VERSION 5.7 ;

UNITS
  TIME NANOSECONDS 1 ;
  CAPACITANCE PICOFARADS 1 ;
  RESISTANCE OHMS 1 ;
  DATABASE MICRONS 1000 ;
END UNITS

MANUFACTURINGGRID 0.005 ;
USEMINSPACING OBS OFF ;

PROPERTYDEFINITIONS
  LAYER LEF58_TYPE STRING ;
END PROPERTYDEFINITIONS

SITE unithd
  SYMMETRY Y ;
  CLASS CORE ;
  SIZE 0.46 BY 2.72 ;
END unithd

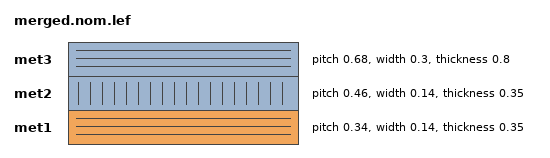
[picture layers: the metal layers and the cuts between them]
LAYER met1
  TYPE ROUTING ;
  DIRECTION HORIZONTAL ;

  PITCH 0.34 ;
  OFFSET 0.17 ;

  WIDTH 0.14 ;                     # Met1 1
  # SPACING 0.14 ;                 # Met1 2
  # SPACING 0.28 RANGE 3.001 100 ; # Met1 3b
  SPACINGTABLE
     PARALLELRUNLENGTH 0
     WIDTH 0 0.14
     WIDTH 3 0.28 ;
  AREA 0.083 ;                     # Met1 6
  THICKNESS 0.35 ;
  MINENCLOSEDAREA 0.14 ;

  ANTENNAMODEL OXIDE1 ;
  ANTENNADIFFSIDEAREARATIO PWL ( ( 0 400 ) ( 0.0125 400 ) ( 0.0225 2609 ) ( 22.5 11600 ) ) ;

  EDGECAPACITANCE 40.567E-6 ;
  CAPACITANCE CPERSQDIST 25.7784E-6 ;
  DCCURRENTDENSITY AVERAGE 2.8 ; # mA/um Iavg_max at Tj = 90oC
  ACCURRENTDENSITY RMS 6.1 ; # mA/um Irms_max at Tj = 90oC
  MAXIMUMDENSITY 70 ;
  DENSITYCHECKWINDOW 700 700 ;
  DENSITYCHECKSTEP 70 ;

  RESISTANCE RPERSQ 0.125 ;
END met1

LAYER met2
  TYPE ROUTING ;
  DIRECTION VERTICAL ;

  PITCH 0.46 ;
  OFFSET 0.23 ;

  WIDTH 0.14 ;                        # Met2 1
  # SPACING  0.14 ;                   # Met2 2
  # SPACING  0.28 RANGE 3.001 100 ;   # Met2 3b
  SPACINGTABLE
     PARALLELRUNLENGTH 0
     WIDTH 0 0.14
     WIDTH 3 0.28 ;
  AREA 0.0676 ;                       # Met2 6
  THICKNESS 0.35 ;
  MINENCLOSEDAREA 0.14 ;

  EDGECAPACITANCE 37.759E-6 ;
  CAPACITANCE CPERSQDIST 16.9423E-6 ;
  RESISTANCE RPERSQ 0.125 ;
  DCCURRENTDENSITY AVERAGE 2.8 ; # mA/um Iavg_max at Tj = 90oC
  ACCURRENTDENSITY RMS 6.1 ; # mA/um Irms_max at Tj = 90oC

  ANTENNAMODEL OXIDE1 ;
  ANTENNADIFFSIDEAREARATIO PWL ( ( 0 400 ) ( 0.0125 400 ) ( 0.0225 2609 ) ( 22.5 11600 ) ) ;

  MAXIMUMDENSITY 70 ;
  DENSITYCHECKWINDOW 700 700 ;
  DENSITYCHECKSTEP 70 ;
END met2

LAYER met3
  TYPE ROUTING ;
  DIRECTION HORIZONTAL ;

  PITCH 0.68 ;
  OFFSET 0.34 ;

  WIDTH 0.3 ;              # Met3 1
  # SPACING 0.3 ;          # Met3 2
  SPACINGTABLE
     PARALLELRUNLENGTH 0
     WIDTH 0 0.3
     WIDTH 3 0.4 ;
  AREA 0.24 ;              # Met3 6
  THICKNESS 0.8 ;

  EDGECAPACITANCE 40.989E-6 ;
  CAPACITANCE CPERSQDIST 12.3729E-6 ;
  RESISTANCE RPERSQ 0.047 ;
  DCCURRENTDENSITY AVERAGE 6.8 ; # mA/um Iavg_max at Tj = 90oC
  ACCURRENTDENSITY RMS 14.9 ; # mA/um Irms_max at Tj = 90oC

  ANTENNAMODEL OXIDE1 ;
  ANTENNADIFFSIDEAREARATIO PWL ( ( 0 400 ) ( 0.0125 400 ) ( 0.0225 2609 ) ( 22.5 11600 ) ) ;

  MAXIMUMDENSITY 70 ;
  DENSITYCHECKWINDOW 700 700 ;
  DENSITYCHECKSTEP 70 ;
END met3

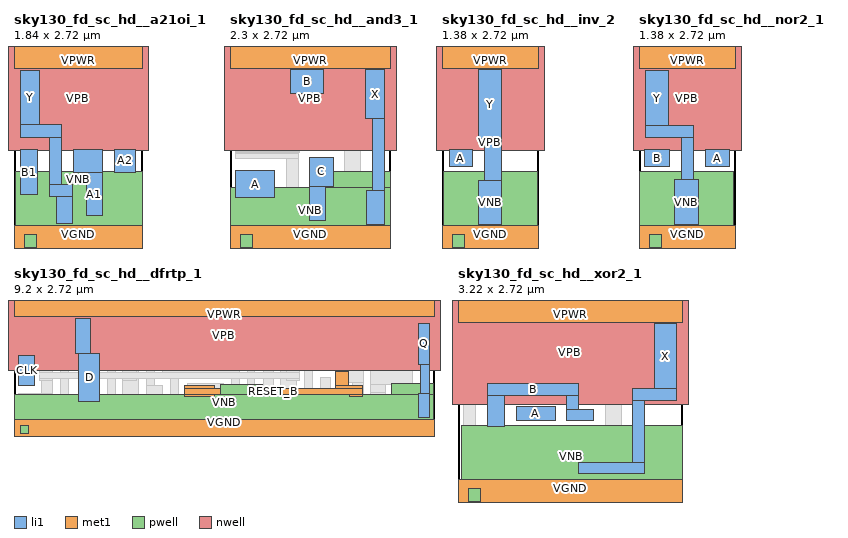
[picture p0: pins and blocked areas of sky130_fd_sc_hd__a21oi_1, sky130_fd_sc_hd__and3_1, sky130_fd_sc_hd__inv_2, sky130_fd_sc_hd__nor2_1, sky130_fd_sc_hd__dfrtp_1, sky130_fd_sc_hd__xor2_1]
MACRO sky130_fd_sc_hd__a21oi_1
  CLASS CORE ;
  FOREIGN sky130_fd_sc_hd__a21oi_1 ;
  ORIGIN 0.000 0.000 ;
  SIZE 1.840 BY 2.720 ;
  SYMMETRY X Y R90 ;
  SITE unithd ;
  PIN A1
    DIRECTION INPUT ;
    USE SIGNAL ;
    ANTENNAGATEAREA 0.247500 ;
    PORT
      LAYER li1 ;
        RECT 0.850 0.995 1.265 1.325 ;
        RECT 1.035 0.375 1.265 0.995 ;
    END
  END A1
  PIN A2
    DIRECTION INPUT ;
    USE SIGNAL ;
    ANTENNAGATEAREA 0.247500 ;
    PORT
      LAYER li1 ;
        RECT 1.445 0.995 1.740 1.325 ;
    END
  END A2
  PIN B1
    DIRECTION INPUT ;
    USE SIGNAL ;
    ANTENNAGATEAREA 0.247500 ;
    PORT
      LAYER li1 ;
        RECT 0.095 0.675 0.335 1.325 ;
    END
  END B1
  PIN VGND
    DIRECTION INOUT ;
    USE GROUND ;
    SHAPE ABUTMENT ;
    PORT
      LAYER met1 ;
        RECT 0.000 -0.240 1.840 0.240 ;
    END
  END VGND
  PIN VNB
    DIRECTION INOUT ;
    USE GROUND ;
    PORT
      LAYER pwell ;
        RECT 0.020 0.105 1.835 1.015 ;
        RECT 0.145 -0.085 0.315 0.105 ;
    END
  END VNB
  PIN VPB
    DIRECTION INOUT ;
    USE POWER ;
    PORT
      LAYER nwell ;
        RECT -0.190 1.305 2.030 2.910 ;
    END
  END VPB
  PIN VPWR
    DIRECTION INOUT ;
    USE POWER ;
    SHAPE ABUTMENT ;
    PORT
      LAYER met1 ;
        RECT 0.000 2.480 1.840 2.960 ;
    END
  END VPWR
  PIN Y
    DIRECTION OUTPUT ;
    USE SIGNAL ;
    ANTENNADIFFAREA 0.447000 ;
    PORT
      LAYER li1 ;
        RECT 0.095 1.685 0.370 2.455 ;
        RECT 0.095 1.495 0.680 1.685 ;
        RECT 0.505 0.825 0.680 1.495 ;
        RECT 0.505 0.645 0.835 0.825 ;
        RECT 0.610 0.265 0.835 0.645 ;
    END
  END Y
  OBS
      LAYER li1 ;
        RECT 0.000 2.635 1.840 2.805 ;
        RECT 0.540 2.025 0.870 2.455 ;
        RECT 1.040 2.195 1.235 2.635 ;
        RECT 1.415 2.025 1.745 2.455 ;
        RECT 0.540 1.855 1.745 2.025 ;
        RECT 0.850 1.525 1.745 1.855 ;
        RECT 0.110 0.085 0.440 0.475 ;
        RECT 1.445 0.085 1.745 0.815 ;
        RECT 0.000 -0.085 1.840 0.085 ;
      LAYER mcon ;
        RECT 0.145 2.635 0.315 2.805 ;
        RECT 0.605 2.635 0.775 2.805 ;
        RECT 1.065 2.635 1.235 2.805 ;
        RECT 1.525 2.635 1.695 2.805 ;
        RECT 0.145 -0.085 0.315 0.085 ;
        RECT 0.605 -0.085 0.775 0.085 ;
        RECT 1.065 -0.085 1.235 0.085 ;
        RECT 1.525 -0.085 1.695 0.085 ;
  END
END sky130_fd_sc_hd__a21oi_1

MACRO sky130_fd_sc_hd__and3_1
  CLASS CORE ;
  FOREIGN sky130_fd_sc_hd__and3_1 ;
  ORIGIN 0.000 0.000 ;
  SIZE 2.300 BY 2.720 ;
  SYMMETRY X Y R90 ;
  SITE unithd ;
  PIN A
    DIRECTION INPUT ;
    USE SIGNAL ;
    ANTENNAGATEAREA 0.126000 ;
    PORT
      LAYER li1 ;
        RECT 0.085 0.635 0.635 1.020 ;
    END
  END A
  PIN B
    DIRECTION INPUT ;
    USE SIGNAL ;
    ANTENNAGATEAREA 0.126000 ;
    PORT
      LAYER li1 ;
        RECT 0.865 2.125 1.345 2.465 ;
    END
  END B
  PIN C
    DIRECTION INPUT ;
    USE SIGNAL ;
    ANTENNAGATEAREA 0.126000 ;
    PORT
      LAYER li1 ;
        RECT 1.145 0.790 1.475 1.215 ;
        RECT 1.145 0.305 1.365 0.790 ;
    END
  END C
  PIN VGND
    DIRECTION INOUT ;
    USE GROUND ;
    SHAPE ABUTMENT ;
    PORT
      LAYER met1 ;
        RECT 0.000 -0.240 2.300 0.240 ;
    END
  END VGND
  PIN VNB
    DIRECTION INOUT ;
    USE GROUND ;
    PORT
      LAYER pwell ;
        RECT 1.375 0.785 2.295 1.015 ;
        RECT 0.005 0.105 2.295 0.785 ;
        RECT 0.145 -0.085 0.315 0.105 ;
    END
  END VNB
  PIN VPB
    DIRECTION INOUT ;
    USE POWER ;
    PORT
      LAYER nwell ;
        RECT -0.190 1.305 2.490 2.910 ;
    END
  END VPB
  PIN VPWR
    DIRECTION INOUT ;
    USE POWER ;
    SHAPE ABUTMENT ;
    PORT
      LAYER met1 ;
        RECT 0.000 2.480 2.300 2.960 ;
    END
  END VPWR
  PIN X
    DIRECTION OUTPUT ;
    USE SIGNAL ;
    ANTENNADIFFAREA 0.429000 ;
    PORT
      LAYER li1 ;
        RECT 1.940 1.765 2.215 2.465 ;
        RECT 2.045 0.735 2.215 1.765 ;
        RECT 1.955 0.255 2.215 0.735 ;
    END
  END X
  OBS
      LAYER li1 ;
        RECT 0.000 2.635 2.300 2.805 ;
        RECT 0.085 2.080 0.690 2.635 ;
        RECT 1.515 2.090 1.770 2.635 ;
        RECT 0.085 1.980 0.700 2.080 ;
        RECT 0.515 1.955 0.700 1.980 ;
        RECT 0.085 1.360 0.345 1.810 ;
        RECT 0.515 1.710 0.845 1.955 ;
        RECT 1.015 1.635 1.770 1.885 ;
        RECT 1.000 1.600 1.770 1.635 ;
        RECT 0.985 1.590 1.770 1.600 ;
        RECT 0.980 1.575 1.875 1.590 ;
        RECT 0.960 1.560 1.875 1.575 ;
        RECT 0.940 1.550 1.875 1.560 ;
        RECT 0.915 1.540 1.875 1.550 ;
        RECT 0.845 1.510 1.875 1.540 ;
        RECT 0.825 1.480 1.875 1.510 ;
        RECT 0.805 1.450 1.875 1.480 ;
        RECT 0.775 1.425 1.875 1.450 ;
        RECT 0.740 1.390 1.875 1.425 ;
        RECT 0.710 1.385 1.875 1.390 ;
        RECT 0.710 1.380 1.100 1.385 ;
        RECT 0.710 1.370 1.075 1.380 ;
        RECT 0.710 1.365 1.060 1.370 ;
        RECT 0.710 1.360 1.045 1.365 ;
        RECT 0.085 1.355 1.045 1.360 ;
        RECT 0.085 1.345 1.035 1.355 ;
        RECT 0.085 1.340 1.025 1.345 ;
        RECT 0.085 1.330 1.015 1.340 ;
        RECT 0.085 1.320 1.010 1.330 ;
        RECT 0.085 1.315 1.005 1.320 ;
        RECT 0.085 1.300 0.995 1.315 ;
        RECT 0.085 1.285 0.990 1.300 ;
        RECT 0.085 1.260 0.980 1.285 ;
        RECT 0.085 1.190 0.975 1.260 ;
        RECT 0.805 0.465 0.975 1.190 ;
        RECT 1.645 0.990 1.875 1.385 ;
        RECT 0.085 0.295 0.975 0.465 ;
        RECT 1.535 0.085 1.785 0.625 ;
        RECT 0.000 -0.085 2.300 0.085 ;
      LAYER mcon ;
        RECT 0.145 2.635 0.315 2.805 ;
        RECT 0.605 2.635 0.775 2.805 ;
        RECT 1.065 2.635 1.235 2.805 ;
        RECT 1.525 2.635 1.695 2.805 ;
        RECT 1.985 2.635 2.155 2.805 ;
        RECT 0.145 -0.085 0.315 0.085 ;
        RECT 0.605 -0.085 0.775 0.085 ;
        RECT 1.065 -0.085 1.235 0.085 ;
        RECT 1.525 -0.085 1.695 0.085 ;
        RECT 1.985 -0.085 2.155 0.085 ;
  END
END sky130_fd_sc_hd__and3_1

MACRO sky130_fd_sc_hd__inv_2
  CLASS CORE ;
  FOREIGN sky130_fd_sc_hd__inv_2 ;
  ORIGIN 0.000 0.000 ;
  SIZE 1.380 BY 2.720 ;
  SYMMETRY X Y R90 ;
  SITE unithd ;
  PIN A
    DIRECTION INPUT ;
    USE SIGNAL ;
    ANTENNAGATEAREA 0.495000 ;
    PORT
      LAYER li1 ;
        RECT 0.105 1.075 0.435 1.325 ;
    END
  END A
  PIN VGND
    DIRECTION INOUT ;
    USE GROUND ;
    SHAPE ABUTMENT ;
    PORT
      LAYER met1 ;
        RECT 0.000 -0.240 1.380 0.240 ;
    END
  END VGND
  PIN VNB
    DIRECTION INOUT ;
    USE GROUND ;
    PORT
      LAYER pwell ;
        RECT 0.015 0.105 1.365 1.015 ;
        RECT 0.145 -0.085 0.315 0.105 ;
    END
  END VNB
  PIN VPB
    DIRECTION INOUT ;
    USE POWER ;
    PORT
      LAYER nwell ;
        RECT -0.190 1.305 1.570 2.910 ;
    END
  END VPB
  PIN VPWR
    DIRECTION INOUT ;
    USE POWER ;
    SHAPE ABUTMENT ;
    PORT
      LAYER met1 ;
        RECT 0.000 2.480 1.380 2.960 ;
    END
  END VPWR
  PIN Y
    DIRECTION OUTPUT ;
    USE SIGNAL ;
    ANTENNADIFFAREA 0.445500 ;
    PORT
      LAYER li1 ;
        RECT 0.525 1.485 0.855 2.465 ;
        RECT 0.605 0.885 0.855 1.485 ;
        RECT 0.525 0.255 0.855 0.885 ;
    END
  END Y
  OBS
      LAYER li1 ;
        RECT 0.000 2.635 1.380 2.805 ;
        RECT 0.125 1.495 0.355 2.635 ;
        RECT 1.025 1.495 1.235 2.635 ;
        RECT 0.125 0.085 0.355 0.905 ;
        RECT 1.025 0.085 1.235 0.905 ;
        RECT 0.000 -0.085 1.380 0.085 ;
      LAYER mcon ;
        RECT 0.145 2.635 0.315 2.805 ;
        RECT 0.605 2.635 0.775 2.805 ;
        RECT 1.065 2.635 1.235 2.805 ;
        RECT 0.145 -0.085 0.315 0.085 ;
        RECT 0.605 -0.085 0.775 0.085 ;
        RECT 1.065 -0.085 1.235 0.085 ;
  END
END sky130_fd_sc_hd__inv_2

MACRO sky130_fd_sc_hd__nor2_1
  CLASS CORE ;
  FOREIGN sky130_fd_sc_hd__nor2_1 ;
  ORIGIN 0.000 0.000 ;
  SIZE 1.380 BY 2.720 ;
  SYMMETRY X Y R90 ;
  SITE unithd ;
  PIN A
    DIRECTION INPUT ;
    USE SIGNAL ;
    ANTENNAGATEAREA 0.247500 ;
    PORT
      LAYER li1 ;
        RECT 0.945 1.075 1.295 1.325 ;
    END
  END A
  PIN B
    DIRECTION INPUT ;
    USE SIGNAL ;
    ANTENNAGATEAREA 0.247500 ;
    PORT
      LAYER li1 ;
        RECT 0.085 1.075 0.435 1.325 ;
    END
  END B
  PIN VGND
    DIRECTION INOUT ;
    USE GROUND ;
    SHAPE ABUTMENT ;
    PORT
      LAYER met1 ;
        RECT 0.000 -0.240 1.380 0.240 ;
    END
  END VGND
  PIN VNB
    DIRECTION INOUT ;
    USE GROUND ;
    PORT
      LAYER pwell ;
        RECT 0.005 0.105 1.355 1.015 ;
        RECT 0.150 -0.085 0.320 0.105 ;
    END
  END VNB
  PIN VPB
    DIRECTION INOUT ;
    USE POWER ;
    PORT
      LAYER nwell ;
        RECT -0.190 1.305 1.570 2.910 ;
    END
  END VPB
  PIN VPWR
    DIRECTION INOUT ;
    USE POWER ;
    SHAPE ABUTMENT ;
    PORT
      LAYER met1 ;
        RECT 0.000 2.480 1.380 2.960 ;
    END
  END VPWR
  PIN Y
    DIRECTION OUTPUT ;
    USE SIGNAL ;
    ANTENNADIFFAREA 0.435500 ;
    PORT
      LAYER li1 ;
        RECT 0.095 1.665 0.425 2.450 ;
        RECT 0.095 1.495 0.775 1.665 ;
        RECT 0.605 0.895 0.775 1.495 ;
        RECT 0.515 0.255 0.845 0.895 ;
    END
  END Y
  OBS
      LAYER li1 ;
        RECT 0.000 2.635 1.380 2.805 ;
        RECT 0.955 1.495 1.285 2.635 ;
        RECT 0.105 0.085 0.345 0.895 ;
        RECT 1.015 0.085 1.285 0.895 ;
        RECT 0.000 -0.085 1.380 0.085 ;
      LAYER mcon ;
        RECT 0.145 2.635 0.315 2.805 ;
        RECT 0.605 2.635 0.775 2.805 ;
        RECT 1.065 2.635 1.235 2.805 ;
        RECT 0.145 -0.085 0.315 0.085 ;
        RECT 0.605 -0.085 0.775 0.085 ;
        RECT 1.065 -0.085 1.235 0.085 ;
  END
END sky130_fd_sc_hd__nor2_1

MACRO sky130_fd_sc_hd__dfrtp_1
  CLASS CORE ;
  FOREIGN sky130_fd_sc_hd__dfrtp_1 ;
  ORIGIN 0.000 0.000 ;
  SIZE 9.200 BY 2.720 ;
  SYMMETRY X Y R90 ;
  SITE unithd ;
  PIN CLK
    DIRECTION INPUT ;
    USE CLOCK ;
    ANTENNAGATEAREA 0.159000 ;
    PORT
      LAYER li1 ;
        RECT 0.090 0.975 0.440 1.625 ;
    END
  END CLK
  PIN D
    DIRECTION INPUT ;
    USE SIGNAL ;
    ANTENNAGATEAREA 0.126000 ;
    PORT
      LAYER li1 ;
        RECT 1.355 1.665 1.680 2.450 ;
        RECT 1.415 0.615 1.875 1.665 ;
    END
  END D
  PIN RESET_B
    DIRECTION INPUT ;
    USE SIGNAL ;
    ANTENNAGATEAREA 0.252000 ;
    PORT
      LAYER met1 ;
        RECT 7.045 0.965 7.335 1.280 ;
        RECT 3.745 0.920 4.395 0.965 ;
        RECT 7.045 0.920 7.635 0.965 ;
        RECT 3.745 0.780 7.635 0.920 ;
        RECT 3.745 0.735 4.395 0.780 ;
        RECT 7.345 0.735 7.635 0.780 ;
    END
  END RESET_B
  PIN VGND
    DIRECTION INOUT ;
    USE GROUND ;
    SHAPE ABUTMENT ;
    PORT
      LAYER met1 ;
        RECT 0.000 -0.240 9.200 0.240 ;
    END
  END VGND
  PIN VNB
    DIRECTION INOUT ;
    USE GROUND ;
    PORT
      LAYER pwell ;
        RECT 4.515 0.785 5.445 1.005 ;
        RECT 8.275 0.785 9.195 1.015 ;
        RECT 0.005 0.105 9.195 0.785 ;
        RECT 0.145 -0.085 0.315 0.105 ;
    END
  END VNB
  PIN VPB
    DIRECTION INOUT ;
    USE POWER ;
    PORT
      LAYER nwell ;
        RECT -0.190 1.305 9.390 2.910 ;
    END
  END VPB
  PIN VPWR
    DIRECTION INOUT ;
    USE POWER ;
    SHAPE ABUTMENT ;
    PORT
      LAYER met1 ;
        RECT 0.000 2.480 9.200 2.960 ;
    END
  END VPWR
  PIN Q
    DIRECTION OUTPUT ;
    USE SIGNAL ;
    ANTENNADIFFAREA 0.429000 ;
    PORT
      LAYER li1 ;
        RECT 8.855 1.445 9.110 2.325 ;
        RECT 8.900 0.795 9.110 1.445 ;
        RECT 8.855 0.265 9.110 0.795 ;
    END
  END Q
  OBS
      LAYER li1 ;
        RECT 0.000 2.635 9.200 2.805 ;
        RECT 0.090 1.965 0.345 2.465 ;
        RECT 0.515 2.135 0.845 2.635 ;
        RECT 0.090 1.795 0.840 1.965 ;
        RECT 0.610 0.805 0.840 1.795 ;
        RECT 0.090 0.635 0.840 0.805 ;
        RECT 0.090 0.345 0.345 0.635 ;
        RECT 0.515 0.085 0.845 0.465 ;
        RECT 1.015 0.345 1.185 2.465 ;
        RECT 1.850 2.175 2.100 2.635 ;
        RECT 2.270 2.135 2.520 2.465 ;
        RECT 2.735 2.135 3.415 2.465 ;
        RECT 2.270 2.005 2.440 2.135 ;
        RECT 2.045 1.835 2.440 2.005 ;
        RECT 2.045 0.475 2.215 1.835 ;
        RECT 2.610 1.575 3.075 1.965 ;
        RECT 2.385 0.765 2.735 1.385 ;
        RECT 2.905 0.985 3.075 1.575 ;
        RECT 3.245 1.355 3.415 2.135 ;
        RECT 3.585 2.035 3.755 2.375 ;
        RECT 3.990 2.205 4.320 2.635 ;
        RECT 4.490 2.035 4.660 2.375 ;
        RECT 4.955 2.175 5.325 2.635 ;
        RECT 3.585 1.865 4.660 2.035 ;
        RECT 5.495 2.005 5.665 2.465 ;
        RECT 5.900 2.125 6.770 2.465 ;
        RECT 6.940 2.175 7.190 2.635 ;
        RECT 5.105 1.835 5.665 2.005 ;
        RECT 5.105 1.695 5.275 1.835 ;
        RECT 3.775 1.525 5.275 1.695 ;
        RECT 5.970 1.665 6.430 1.955 ;
        RECT 3.245 1.185 4.935 1.355 ;
        RECT 2.905 0.765 3.260 0.985 ;
        RECT 3.430 0.475 3.600 1.185 ;
        RECT 3.805 0.765 4.595 1.015 ;
        RECT 4.765 1.005 4.935 1.185 ;
        RECT 5.105 0.835 5.275 1.525 ;
        RECT 1.545 0.085 1.875 0.445 ;
        RECT 2.045 0.305 2.540 0.475 ;
        RECT 2.745 0.305 3.600 0.475 ;
        RECT 4.475 0.085 4.805 0.545 ;
        RECT 5.015 0.445 5.275 0.835 ;
        RECT 5.465 1.655 6.430 1.665 ;
        RECT 6.600 1.745 6.770 2.125 ;
        RECT 7.360 2.085 7.530 2.375 ;
        RECT 7.710 2.255 8.040 2.635 ;
        RECT 7.360 1.915 8.160 2.085 ;
        RECT 5.465 1.495 6.140 1.655 ;
        RECT 6.600 1.575 7.820 1.745 ;
        RECT 5.465 0.705 5.675 1.495 ;
        RECT 6.600 1.485 6.770 1.575 ;
        RECT 5.845 0.705 6.195 1.325 ;
        RECT 6.365 1.315 6.770 1.485 ;
        RECT 6.365 0.535 6.535 1.315 ;
        RECT 6.705 0.865 6.925 1.145 ;
        RECT 7.105 1.035 7.645 1.405 ;
        RECT 7.990 1.325 8.160 1.915 ;
        RECT 8.380 1.495 8.685 2.635 ;
        RECT 7.990 1.295 8.730 1.325 ;
        RECT 6.705 0.695 7.235 0.865 ;
        RECT 5.015 0.275 5.365 0.445 ;
        RECT 5.585 0.255 6.535 0.535 ;
        RECT 6.705 0.085 6.895 0.525 ;
        RECT 7.065 0.465 7.235 0.695 ;
        RECT 7.405 0.635 7.645 1.035 ;
        RECT 7.815 0.995 8.730 1.295 ;
        RECT 7.815 0.820 8.140 0.995 ;
        RECT 7.815 0.465 8.135 0.820 ;
        RECT 7.065 0.295 8.135 0.465 ;
        RECT 8.380 0.085 8.685 0.545 ;
        RECT 0.000 -0.085 9.200 0.085 ;
      LAYER mcon ;
        RECT 0.145 2.635 0.315 2.805 ;
        RECT 0.605 2.635 0.775 2.805 ;
        RECT 1.065 2.635 1.235 2.805 ;
        RECT 1.525 2.635 1.695 2.805 ;
        RECT 1.985 2.635 2.155 2.805 ;
        RECT 2.445 2.635 2.615 2.805 ;
        RECT 2.905 2.635 3.075 2.805 ;
        RECT 3.365 2.635 3.535 2.805 ;
        RECT 3.825 2.635 3.995 2.805 ;
        RECT 4.285 2.635 4.455 2.805 ;
        RECT 4.745 2.635 4.915 2.805 ;
        RECT 5.205 2.635 5.375 2.805 ;
        RECT 5.665 2.635 5.835 2.805 ;
        RECT 6.125 2.635 6.295 2.805 ;
        RECT 6.585 2.635 6.755 2.805 ;
        RECT 7.045 2.635 7.215 2.805 ;
        RECT 7.505 2.635 7.675 2.805 ;
        RECT 7.965 2.635 8.135 2.805 ;
        RECT 8.425 2.635 8.595 2.805 ;
        RECT 8.885 2.635 9.055 2.805 ;
        RECT 0.610 1.105 0.780 1.275 ;
        RECT 1.015 1.785 1.185 1.955 ;
        RECT 2.905 1.785 3.075 1.955 ;
        RECT 2.445 1.105 2.615 1.275 ;
        RECT 6.025 1.785 6.195 1.955 ;
        RECT 4.165 0.765 4.335 0.935 ;
        RECT 6.025 1.105 6.195 1.275 ;
        RECT 7.105 1.080 7.275 1.250 ;
        RECT 7.405 0.765 7.575 0.935 ;
        RECT 0.145 -0.085 0.315 0.085 ;
        RECT 0.605 -0.085 0.775 0.085 ;
        RECT 1.065 -0.085 1.235 0.085 ;
        RECT 1.525 -0.085 1.695 0.085 ;
        RECT 1.985 -0.085 2.155 0.085 ;
        RECT 2.445 -0.085 2.615 0.085 ;
        RECT 2.905 -0.085 3.075 0.085 ;
        RECT 3.365 -0.085 3.535 0.085 ;
        RECT 3.825 -0.085 3.995 0.085 ;
        RECT 4.285 -0.085 4.455 0.085 ;
        RECT 4.745 -0.085 4.915 0.085 ;
        RECT 5.205 -0.085 5.375 0.085 ;
        RECT 5.665 -0.085 5.835 0.085 ;
        RECT 6.125 -0.085 6.295 0.085 ;
        RECT 6.585 -0.085 6.755 0.085 ;
        RECT 7.045 -0.085 7.215 0.085 ;
        RECT 7.505 -0.085 7.675 0.085 ;
        RECT 7.965 -0.085 8.135 0.085 ;
        RECT 8.425 -0.085 8.595 0.085 ;
        RECT 8.885 -0.085 9.055 0.085 ;
      LAYER met1 ;
        RECT 0.955 1.940 1.245 1.985 ;
        RECT 2.845 1.940 3.135 1.985 ;
        RECT 5.965 1.940 6.255 1.985 ;
        RECT 0.955 1.800 6.255 1.940 ;
        RECT 0.955 1.755 1.245 1.800 ;
        RECT 2.845 1.755 3.135 1.800 ;
        RECT 5.965 1.755 6.255 1.800 ;
        RECT 0.550 1.260 0.840 1.305 ;
        RECT 2.385 1.260 2.675 1.305 ;
        RECT 5.965 1.260 6.255 1.305 ;
        RECT 0.550 1.120 6.255 1.260 ;
        RECT 0.550 1.075 0.840 1.120 ;
        RECT 2.385 1.075 2.675 1.120 ;
        RECT 5.965 1.075 6.255 1.120 ;
  END
END sky130_fd_sc_hd__dfrtp_1

MACRO sky130_fd_sc_hd__xor2_1
  CLASS CORE ;
  FOREIGN sky130_fd_sc_hd__xor2_1 ;
  ORIGIN 0.000 0.000 ;
  SIZE 3.220 BY 2.720 ;
  SYMMETRY X Y R90 ;
  SITE unithd ;
  PIN A
    DIRECTION INPUT ;
    USE SIGNAL ;
    ANTENNAGATEAREA 0.495000 ;
    PORT
      LAYER li1 ;
        RECT 0.840 1.075 1.390 1.275 ;
    END
  END A
  PIN B
    DIRECTION INPUT ;
    USE SIGNAL ;
    ANTENNAGATEAREA 0.495000 ;
    PORT
      LAYER li1 ;
        RECT 0.425 1.445 1.730 1.615 ;
        RECT 0.425 0.995 0.670 1.445 ;
        RECT 1.560 1.245 1.730 1.445 ;
        RECT 1.560 1.075 1.935 1.245 ;
    END
  END B
  PIN VGND
    DIRECTION INOUT ;
    USE GROUND ;
    SHAPE ABUTMENT ;
    PORT
      LAYER met1 ;
        RECT 0.000 -0.240 3.220 0.240 ;
    END
  END VGND
  PIN VNB
    DIRECTION INOUT ;
    USE GROUND ;
    PORT
      LAYER pwell ;
        RECT 0.045 0.105 3.215 1.015 ;
        RECT 0.145 -0.085 0.315 0.105 ;
    END
  END VNB
  PIN VPB
    DIRECTION INOUT ;
    USE POWER ;
    PORT
      LAYER nwell ;
        RECT -0.190 1.305 3.410 2.910 ;
    END
  END VPB
  PIN VPWR
    DIRECTION INOUT ;
    USE POWER ;
    SHAPE ABUTMENT ;
    PORT
      LAYER met1 ;
        RECT 0.000 2.480 3.220 2.960 ;
    END
  END VPWR
  PIN X
    DIRECTION OUTPUT ;
    USE SIGNAL ;
    ANTENNADIFFAREA 0.800500 ;
    PORT
      LAYER li1 ;
        RECT 2.815 1.535 3.135 2.465 ;
        RECT 2.505 1.365 3.135 1.535 ;
        RECT 2.505 0.485 2.675 1.365 ;
        RECT 1.720 0.315 2.675 0.485 ;
    END
  END X
  OBS
      LAYER li1 ;
        RECT 0.000 2.635 3.220 2.805 ;
        RECT 0.085 1.785 0.465 2.465 ;
        RECT 1.055 1.785 1.225 2.635 ;
        RECT 1.395 1.955 1.725 2.465 ;
        RECT 1.895 2.125 2.065 2.635 ;
        RECT 2.235 1.955 2.635 2.465 ;
        RECT 1.395 1.785 2.635 1.955 ;
        RECT 0.085 0.825 0.255 1.785 ;
        RECT 2.105 0.825 2.335 1.325 ;
        RECT 0.085 0.655 2.335 0.825 ;
        RECT 0.135 0.085 0.465 0.475 ;
        RECT 0.635 0.335 0.805 0.655 ;
        RECT 0.975 0.085 1.305 0.475 ;
        RECT 2.845 0.085 3.135 0.920 ;
        RECT 0.000 -0.085 3.220 0.085 ;
      LAYER mcon ;
        RECT 0.145 2.635 0.315 2.805 ;
        RECT 0.605 2.635 0.775 2.805 ;
        RECT 1.065 2.635 1.235 2.805 ;
        RECT 1.525 2.635 1.695 2.805 ;
        RECT 1.985 2.635 2.155 2.805 ;
        RECT 2.445 2.635 2.615 2.805 ;
        RECT 2.905 2.635 3.075 2.805 ;
        RECT 0.145 -0.085 0.315 0.085 ;
        RECT 0.605 -0.085 0.775 0.085 ;
        RECT 1.065 -0.085 1.235 0.085 ;
        RECT 1.525 -0.085 1.695 0.085 ;
        RECT 1.985 -0.085 2.155 0.085 ;
        RECT 2.445 -0.085 2.615 0.085 ;
        RECT 2.905 -0.085 3.075 0.085 ;
  END
END sky130_fd_sc_hd__xor2_1
END LIBRARY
